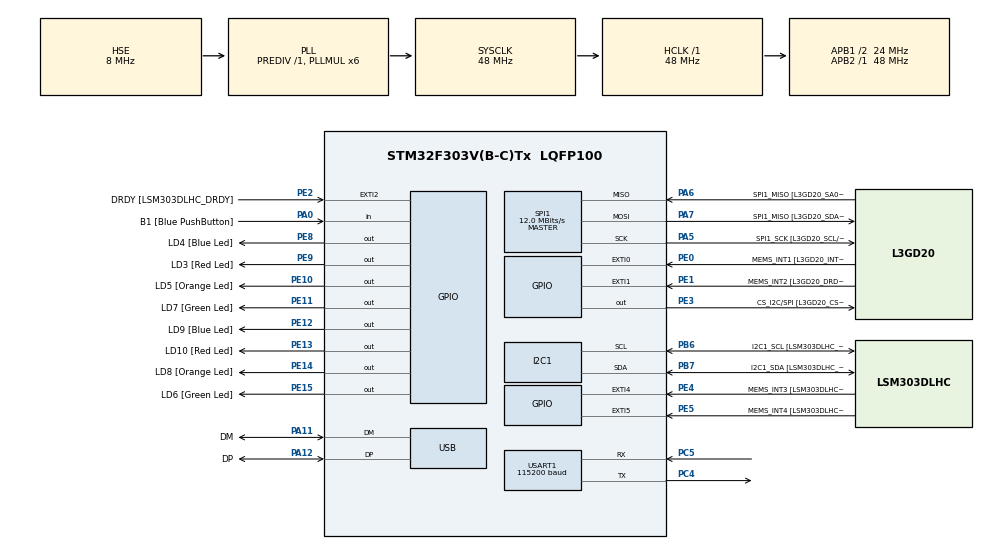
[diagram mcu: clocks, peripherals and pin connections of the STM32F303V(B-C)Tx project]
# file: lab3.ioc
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I2C1.Timing=0x00201D2B
I2C1.Timing-I2C=0x2000090E
Mcu.Family=STM32F3
Mcu.Name=STM32F303V(B-C)Tx
Mcu.Package=LQFP100
NVIC.PriorityGroup=NVIC_PRIORITYGROUP_0
NVIC.USB_LP_CAN_RX0_IRQn=true\:0\:0\:false\:false\:true\:false\:true\:true
PA0.GPIO_Label=B1 [Blue PushButton]
PA0.Signal=GPIO_Input
PA11.GPIO_Label=DM
PA11.Mode=Device
PA11.Signal=USB_DM
PA12.GPIO_Label=DP
PA12.Mode=Device
PA12.Signal=USB_DP
PA13.GPIO_Label=SWDIO
PA13.Mode=Serial_Wire
PA13.Signal=SYS_JTMS-SWDIO
PA14.GPIO_Label=SWCLK
PA14.Mode=Serial_Wire
PA14.Signal=SYS_JTCK-SWCLK
PA5.GPIO_Label=SPI1_SCK [L3GD20_SCL/SPC]
PA5.Mode=Full_Duplex_Master
PA5.Signal=SPI1_SCK
PA6.GPIO_Label=SPI1_MISO [L3GD20_SA0/SDO]
PA6.Mode=Full_Duplex_Master
PA6.Signal=SPI1_MISO
PA7.GPIO_Label=SPI1_MISO [L3GD20_SDA/SDI/SDO]
PA7.Mode=Full_Duplex_Master
PA7.Signal=SPI1_MOSI
PB3.GPIO_Label=SWO
PB3.Signal=SYS_JTDO-TRACESWO
PB6.GPIO_Label=I2C1_SCL [LSM303DLHC_SCL]
PB6.GPIO_Pu=GPIO_PULLUP
PB6.Mode=I2C
PB6.Signal=I2C1_SCL
PB7.GPIO_Label=I2C1_SDA [LSM303DLHC_SDA]
PB7.GPIO_Pu=GPIO_PULLUP
PB7.Mode=I2C
PB7.Signal=I2C1_SDA
PC14-OSC32_IN.GPIO_Label=OSC32_IN
PC14-OSC32_IN.Signal=RCC_OSC32_IN
PC15-OSC32_OUT.GPIO_Label=OSC32_OUT
PC15-OSC32_OUT.Signal=RCC_OSC32_OUT
PC4.Mode=Asynchronous
PC4.Signal=USART1_TX
PC5.Mode=Asynchronous
PC5.Signal=USART1_RX
PE0.GPIO_Label=MEMS_INT1 [L3GD20_INT1]
PE0.GPIO_ModeDefaultEXTI=GPIO_MODE_EVT_RISING
PE0.Signal=GPXTI0
PE1.GPIO_Label=MEMS_INT2 [L3GD20_DRDY/INT2]
PE1.GPIO_ModeDefaultEXTI=GPIO_MODE_EVT_RISING
PE1.Signal=GPXTI1
PE10.GPIO_Label=LD5 [Orange Led]
PE10.Signal=GPIO_Output
PE11.GPIO_Label=LD7 [Green Led]
PE11.Signal=GPIO_Output
PE12.GPIO_Label=LD9 [Blue Led]
PE12.Signal=GPIO_Output
PE13.GPIO_Label=LD10 [Red Led]
PE13.Signal=GPIO_Output
PE14.GPIO_Label=LD8 [Orange Led]
PE14.Signal=GPIO_Output
PE15.GPIO_Label=LD6 [Green Led]
PE15.Signal=GPIO_Output
PE2.GPIO_Label=DRDY [LSM303DLHC_DRDY]
PE2.GPIO_ModeDefaultEXTI=GPIO_MODE_EVT_RISING
PE2.Signal=GPXTI2
PE3.GPIO_Label=CS_I2C/SPI [L3GD20_CS_I2C/SPI]
PE3.Signal=GPIO_Output
PE4.GPIO_Label=MEMS_INT3 [LSM303DLHC_INT1]
PE4.GPIO_ModeDefaultEXTI=GPIO_MODE_EVT_RISING
PE4.Signal=GPXTI4
PE5.GPIO_Label=MEMS_INT4 [LSM303DLHC_INT2]
PE5.GPIO_ModeDefaultEXTI=GPIO_MODE_EVT_RISING
PE5.Signal=GPXTI5
PE8.GPIO_Label=LD4 [Blue Led]
PE8.Signal=GPIO_Output
PE9.GPIO_Label=LD3 [Red Led]
PE9.Signal=GPIO_Output
PF0-OSC_IN.GPIO_Label=OSC_IN
PF0-OSC_IN.Mode=HSE-External-Clock-Source
PF0-OSC_IN.Signal=RCC_OSC_IN
PF1-OSC_OUT.GPIO_Label=OSC_OUT
PF1-OSC_OUT.Signal=RCC_OSC_OUT
ProjectManager.HeapSize=0x200
ProjectManager.StackSize=0x400
ProjectManager.TargetToolchain=CMake
RCC.AHBFreq_Value=48000000
RCC.APB1CLKDivider=RCC_HCLK_DIV2
RCC.APB1Freq_Value=24000000
RCC.APB1TimFreq_Value=48000000
RCC.APB2Freq_Value=48000000
RCC.APB2TimFreq_Value=48000000
RCC.CortexFreq_Value=48000000
RCC.HCLKFreq_Value=48000000
RCC.HSE_VALUE=8000000
RCC.HSI_VALUE=8000000
RCC.LSE_VALUE=32768
RCC.PLLMUL=RCC_PLL_MUL6
RCC.SYSCLKFreq_VALUE=48000000
RCC.SYSCLKSourceVirtual=RCC_SYSCLKSOURCE_PLLCLK
RCC.USBFreq_Value=48000000
SPI1.BaudRatePrescaler=SPI_BAUDRATEPRESCALER_4
SPI1.BaudRatePrescaler-Full_Duplex_Master=SPI_BAUDRATEPRESCALER_2
SPI1.CalculateBaudRate=12.0 MBits/s
SPI1.CalculateBaudRate-Full_Duplex_Master=24.0 MBits/s
SPI1.Direction=SPI_DIRECTION_2LINES
SPI1.Mode=SPI_MODE_MASTER
SPI1.Mode-Full_Duplex_Master=SPI_MODE_MASTER
SPI1.VirtualType=VM_MASTER
USART1.BaudRate=115200
USART1.VirtualMode-Asynchronous=VM_ASYNC
USB_DEVICE.CLASS_NAME_FS=CDC
USB_DEVICE.VirtualMode=Cdc
USB_DEVICE.VirtualModeFS=Cdc_FS
VP_USB_DEVICE_VS_USB_DEVICE_CDC_FS.Mode=CDC_FS
board=STM32F3DISCOVERY

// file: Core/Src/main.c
/* USER CODE BEGIN Header */
/**
  ******************************************************************************
  * @file           : main.c
  * @brief          : Main program body
  ******************************************************************************
  * @attention
  *
  * Copyright (c) 2026 STMicroelectronics.
  * All rights reserved.
  *
  * This software is licensed under terms that can be found in the LICENSE file
  * in the root directory of this software component.
  * If no LICENSE file comes with this software, it is provided AS-IS.
  *
  ******************************************************************************
  */
/* USER CODE END Header */
#include "main.h"
#include "usb_device.h"

I2C_HandleTypeDef hi2c1;

SPI_HandleTypeDef hspi1;

UART_HandleTypeDef huart1;

void SystemClock_Config(void);
static void MX_GPIO_Init(void);
static void MX_I2C1_Init(void);
static void MX_SPI1_Init(void);
static void MX_USART1_UART_Init(void);

void display_num(int i){
  if (i == 0) {
          HAL_GPIO_WritePin(GPIOA, GPIO_PIN_1 | GPIO_PIN_2 | GPIO_PIN_3 | GPIO_PIN_4, GPIO_PIN_RESET); // a,b,d,e
          HAL_GPIO_WritePin(GPIOF, GPIO_PIN_4, GPIO_PIN_RESET);  // c
          HAL_GPIO_WritePin(GPIOC, GPIO_PIN_0, GPIO_PIN_RESET);  // f
          HAL_GPIO_WritePin(GPIOB, GPIO_PIN_1, GPIO_PIN_SET);    // g
      }

      if (i == 1) {
          HAL_GPIO_WritePin(GPIOA, GPIO_PIN_1 | GPIO_PIN_2 | GPIO_PIN_4, GPIO_PIN_SET);  // a,e,d
          HAL_GPIO_WritePin(GPIOA, GPIO_PIN_3, GPIO_PIN_RESET); // b
          HAL_GPIO_WritePin(GPIOF, GPIO_PIN_4, GPIO_PIN_RESET); // c
          HAL_GPIO_WritePin(GPIOC, GPIO_PIN_0, GPIO_PIN_SET);   // f
          HAL_GPIO_WritePin(GPIOB, GPIO_PIN_1, GPIO_PIN_SET);   // g
      }

      if (i == 2) {
          HAL_GPIO_WritePin(GPIOA, GPIO_PIN_1 | GPIO_PIN_3 | GPIO_PIN_4, GPIO_PIN_RESET); // a,b,d
          HAL_GPIO_WritePin(GPIOA, GPIO_PIN_2, GPIO_PIN_RESET);  // e
          HAL_GPIO_WritePin(GPIOF, GPIO_PIN_4, GPIO_PIN_SET);  // c
          HAL_GPIO_WritePin(GPIOC, GPIO_PIN_0, GPIO_PIN_SET);    // f
          HAL_GPIO_WritePin(GPIOB, GPIO_PIN_1, GPIO_PIN_RESET);  // g
      }

      if (i == 3) {
          HAL_GPIO_WritePin(GPIOA, GPIO_PIN_1 | GPIO_PIN_3 | GPIO_PIN_4, GPIO_PIN_RESET); // a,b,d
          HAL_GPIO_WritePin(GPIOA, GPIO_PIN_2, GPIO_PIN_SET);    // e
          HAL_GPIO_WritePin(GPIOF, GPIO_PIN_4, GPIO_PIN_RESET);  // c
          HAL_GPIO_WritePin(GPIOC, GPIO_PIN_0, GPIO_PIN_SET);  // f
          HAL_GPIO_WritePin(GPIOB, GPIO_PIN_1, GPIO_PIN_RESET);  // g
      }

      if (i == 4) {
          HAL_GPIO_WritePin(GPIOA, GPIO_PIN_1, GPIO_PIN_SET);
          HAL_GPIO_WritePin(GPIOA, GPIO_PIN_3, GPIO_PIN_RESET); // a,b
          HAL_GPIO_WritePin(GPIOA, GPIO_PIN_4 | GPIO_PIN_2, GPIO_PIN_SET);   // d,e
          HAL_GPIO_WritePin(GPIOF, GPIO_PIN_4, GPIO_PIN_RESET);               // c
          HAL_GPIO_WritePin(GPIOC, GPIO_PIN_0, GPIO_PIN_RESET);               // f
          HAL_GPIO_WritePin(GPIOB, GPIO_PIN_1, GPIO_PIN_RESET);               // g
      }

      if (i == 5) {
          HAL_GPIO_WritePin(GPIOA, GPIO_PIN_1 | GPIO_PIN_4, GPIO_PIN_RESET); // a,d
          HAL_GPIO_WritePin(GPIOA, GPIO_PIN_2 | GPIO_PIN_3, GPIO_PIN_SET);   // e,b
          HAL_GPIO_WritePin(GPIOF, GPIO_PIN_4, GPIO_PIN_RESET);               // c
          HAL_GPIO_WritePin(GPIOC, GPIO_PIN_0, GPIO_PIN_RESET);               // f
          HAL_GPIO_WritePin(GPIOB, GPIO_PIN_1, GPIO_PIN_RESET);               // g
      }

      if (i == 6) {
          HAL_GPIO_WritePin(GPIOA, GPIO_PIN_1 | GPIO_PIN_4, GPIO_PIN_RESET); // a,d
          HAL_GPIO_WritePin(GPIOA, GPIO_PIN_3, GPIO_PIN_SET);
          HAL_GPIO_WritePin(GPIOA, GPIO_PIN_2, GPIO_PIN_RESET);   // e,b
          HAL_GPIO_WritePin(GPIOF, GPIO_PIN_4, GPIO_PIN_RESET);               // c
          HAL_GPIO_WritePin(GPIOC, GPIO_PIN_0, GPIO_PIN_RESET);               // f
          HAL_GPIO_WritePin(GPIOB, GPIO_PIN_1, GPIO_PIN_RESET);               // g
      }

      if (i == 7) {
          HAL_GPIO_WritePin(GPIOA, GPIO_PIN_1 | GPIO_PIN_3, GPIO_PIN_RESET);
          HAL_GPIO_WritePin(GPIOA, GPIO_PIN_4 | GPIO_PIN_2, GPIO_PIN_SET); // a,b,c,d
          HAL_GPIO_WritePin(GPIOF, GPIO_PIN_4, GPIO_PIN_RESET);               // c
          HAL_GPIO_WritePin(GPIOC, GPIO_PIN_0, GPIO_PIN_SET);                 // f
          HAL_GPIO_WritePin(GPIOB, GPIO_PIN_1, GPIO_PIN_SET);                 // g
      }

      if (i == 8) {
          HAL_GPIO_WritePin(GPIOA, GPIO_PIN_1 | GPIO_PIN_2 | GPIO_PIN_3 | GPIO_PIN_4, GPIO_PIN_RESET); // a,b,d,e
          HAL_GPIO_WritePin(GPIOF, GPIO_PIN_4, GPIO_PIN_RESET);               // c
          HAL_GPIO_WritePin(GPIOC, GPIO_PIN_0, GPIO_PIN_RESET);               // f
          HAL_GPIO_WritePin(GPIOB, GPIO_PIN_1, GPIO_PIN_RESET);               // g
      }

      if (i == 9) {
          HAL_GPIO_WritePin(GPIOA, GPIO_PIN_1 | GPIO_PIN_3 | GPIO_PIN_4, GPIO_PIN_RESET); // a,b,d
          HAL_GPIO_WritePin(GPIOA, GPIO_PIN_2, GPIO_PIN_SET);    // e
          HAL_GPIO_WritePin(GPIOF, GPIO_PIN_4, GPIO_PIN_RESET);  // c
          HAL_GPIO_WritePin(GPIOC, GPIO_PIN_0, GPIO_PIN_RESET);  // f
          HAL_GPIO_WritePin(GPIOB, GPIO_PIN_1, GPIO_PIN_RESET);  // g
      }

      if (i == 10) { // A
          HAL_GPIO_WritePin(GPIOA, GPIO_PIN_1 | GPIO_PIN_3 | GPIO_PIN_2, GPIO_PIN_RESET); // a,b,e
          HAL_GPIO_WritePin(GPIOA, GPIO_PIN_4, GPIO_PIN_SET);    // d
          HAL_GPIO_WritePin(GPIOF, GPIO_PIN_4, GPIO_PIN_RESET);  // c
          HAL_GPIO_WritePin(GPIOC, GPIO_PIN_0, GPIO_PIN_RESET);  // f
          HAL_GPIO_WritePin(GPIOB, GPIO_PIN_1, GPIO_PIN_RESET);  // g
      }

      if (i == 11) { // b
          HAL_GPIO_WritePin(GPIOA, GPIO_PIN_4, GPIO_PIN_RESET);  // d
          HAL_GPIO_WritePin(GPIOA, GPIO_PIN_1 | GPIO_PIN_3, GPIO_PIN_SET);
          HAL_GPIO_WritePin(GPIOA, GPIO_PIN_2, GPIO_PIN_RESET); // a,b,e
          HAL_GPIO_WritePin(GPIOF, GPIO_PIN_4, GPIO_PIN_RESET);  // c
          HAL_GPIO_WritePin(GPIOC, GPIO_PIN_0, GPIO_PIN_RESET);  // f
          HAL_GPIO_WritePin(GPIOB, GPIO_PIN_1, GPIO_PIN_RESET);  // g
      }

      if (i == 12) { // C
          HAL_GPIO_WritePin(GPIOA, GPIO_PIN_1 | GPIO_PIN_4 | GPIO_PIN_2, GPIO_PIN_RESET); // a,d,e
          HAL_GPIO_WritePin(GPIOA, GPIO_PIN_3, GPIO_PIN_SET);    // b
          HAL_GPIO_WritePin(GPIOF, GPIO_PIN_4, GPIO_PIN_SET);    // c
          HAL_GPIO_WritePin(GPIOC, GPIO_PIN_0, GPIO_PIN_RESET);  // f
          HAL_GPIO_WritePin(GPIOB, GPIO_PIN_1, GPIO_PIN_SET);    // g
      }

      if (i == 13) { // d
          HAL_GPIO_WritePin(GPIOA, GPIO_PIN_3 | GPIO_PIN_4 | GPIO_PIN_2, GPIO_PIN_RESET); // b,d,e
          HAL_GPIO_WritePin(GPIOA, GPIO_PIN_1, GPIO_PIN_SET);    // a
          HAL_GPIO_WritePin(GPIOF, GPIO_PIN_4, GPIO_PIN_RESET);  // c
          HAL_GPIO_WritePin(GPIOC, GPIO_PIN_0, GPIO_PIN_SET);    // f
          HAL_GPIO_WritePin(GPIOB, GPIO_PIN_1, GPIO_PIN_RESET);  // g
      }

      if (i == 14) { // E
          HAL_GPIO_WritePin(GPIOA, GPIO_PIN_1 | GPIO_PIN_4 | GPIO_PIN_2, GPIO_PIN_RESET); // a,d,e
          HAL_GPIO_WritePin(GPIOA, GPIO_PIN_3, GPIO_PIN_SET);    // b
          HAL_GPIO_WritePin(GPIOF, GPIO_PIN_4, GPIO_PIN_SET);    // c
          HAL_GPIO_WritePin(GPIOC, GPIO_PIN_0, GPIO_PIN_RESET);  // f
          HAL_GPIO_WritePin(GPIOB, GPIO_PIN_1, GPIO_PIN_RESET);  // g
      }

      if (i == 15) { // F
          HAL_GPIO_WritePin(GPIOA, GPIO_PIN_1 | GPIO_PIN_2, GPIO_PIN_RESET); // a,d,e
          HAL_GPIO_WritePin(GPIOA, GPIO_PIN_4, GPIO_PIN_SET);
          HAL_GPIO_WritePin(GPIOA, GPIO_PIN_3, GPIO_PIN_SET);    // b
          HAL_GPIO_WritePin(GPIOF, GPIO_PIN_4, GPIO_PIN_SET);    // c
          HAL_GPIO_WritePin(GPIOC, GPIO_PIN_0, GPIO_PIN_RESET);  // f
          HAL_GPIO_WritePin(GPIOB, GPIO_PIN_1, GPIO_PIN_RESET);    // g
      }
}

int main(void)
{

  /* MCU Configuration--------------------------------------------------------*/

  /* Reset of all peripherals, Initializes the Flash interface and the Systick. */
  HAL_Init();

  /* Configure the system clock */
  SystemClock_Config();

  /* Initialize all configured peripherals */
  MX_GPIO_Init();
  MX_I2C1_Init();
  MX_SPI1_Init();
  MX_USART1_UART_Init();
  MX_USB_DEVICE_Init();
  /*HAL_GPIO_WritePin(GPIOA, GPIO_PIN_1 | GPIO_PIN_2 | GPIO_PIN_3 | GPIO_PIN_4, GPIO_PIN_RESET);
  HAL_GPIO_WritePin(GPIOF, GPIO_PIN_4, GPIO_PIN_RESET);
  HAL_GPIO_WritePin(GPIOC, GPIO_PIN_0, GPIO_PIN_RESET);
  HAL_GPIO_WritePin(GPIOB, GPIO_PIN_1, GPIO_PIN_RESET);*/

  //a = PA1 b = PA3 c = PF4 d = PA4 e = PA2 f = PC0 g = PB1
  /* Infinite loop */
  /* USER CODE BEGIN WHILE */

  int n = 0;
  while (1)
  {
    display_num(n);
    /* USER CODE END WHILE */

    if(HAL_GPIO_ReadPin(GPIOB, GPIO_PIN_4) == GPIO_PIN_SET) { // active-low
        HAL_Delay(50); // debounce
        if(HAL_GPIO_ReadPin(GPIOB, GPIO_PIN_4) == GPIO_PIN_SET) {
            n = (rand() % 6) + 1;
            while(HAL_GPIO_ReadPin(GPIOB, GPIO_PIN_4) == GPIO_PIN_SET); // wait for release
            HAL_Delay(50); // debounce
        }
    }
  }

}

void SystemClock_Config(void)
{
  RCC_OscInitTypeDef RCC_OscInitStruct = {0};
  RCC_ClkInitTypeDef RCC_ClkInitStruct = {0};
  RCC_PeriphCLKInitTypeDef PeriphClkInit = {0};

  /** Initializes the RCC Oscillators according to the specified parameters
  * in the RCC_OscInitTypeDef structure.
  */
  RCC_OscInitStruct.OscillatorType = RCC_OSCILLATORTYPE_HSI|RCC_OSCILLATORTYPE_HSE;
  RCC_OscInitStruct.HSEState = RCC_HSE_BYPASS;
  RCC_OscInitStruct.HSEPredivValue = RCC_HSE_PREDIV_DIV1;
  RCC_OscInitStruct.HSIState = RCC_HSI_ON;
  RCC_OscInitStruct.HSICalibrationValue = RCC_HSICALIBRATION_DEFAULT;
  RCC_OscInitStruct.PLL.PLLState = RCC_PLL_ON;
  RCC_OscInitStruct.PLL.PLLSource = RCC_PLLSOURCE_HSE;
  RCC_OscInitStruct.PLL.PLLMUL = RCC_PLL_MUL6;
  if (HAL_RCC_OscConfig(&RCC_OscInitStruct) != HAL_OK)
  {
    Error_Handler();
  }

  /** Initializes the CPU, AHB and APB buses clocks
  */
  RCC_ClkInitStruct.ClockType = RCC_CLOCKTYPE_HCLK|RCC_CLOCKTYPE_SYSCLK
                              |RCC_CLOCKTYPE_PCLK1|RCC_CLOCKTYPE_PCLK2;
  RCC_ClkInitStruct.SYSCLKSource = RCC_SYSCLKSOURCE_PLLCLK;
  RCC_ClkInitStruct.AHBCLKDivider = RCC_SYSCLK_DIV1;
  RCC_ClkInitStruct.APB1CLKDivider = RCC_HCLK_DIV2;
  RCC_ClkInitStruct.APB2CLKDivider = RCC_HCLK_DIV1;

  if (HAL_RCC_ClockConfig(&RCC_ClkInitStruct, FLASH_LATENCY_1) != HAL_OK)
  {
    Error_Handler();
  }
  PeriphClkInit.PeriphClockSelection = RCC_PERIPHCLK_USB|RCC_PERIPHCLK_USART1
                              |RCC_PERIPHCLK_I2C1;
  PeriphClkInit.Usart1ClockSelection = RCC_USART1CLKSOURCE_PCLK2;
  PeriphClkInit.I2c1ClockSelection = RCC_I2C1CLKSOURCE_HSI;
  PeriphClkInit.USBClockSelection = RCC_USBCLKSOURCE_PLL;
  if (HAL_RCCEx_PeriphCLKConfig(&PeriphClkInit) != HAL_OK)
  {
    Error_Handler();
  }
}

static void MX_I2C1_Init(void)
{

  hi2c1.Instance = I2C1;
  hi2c1.Init.Timing = 0x00201D2B;
  hi2c1.Init.OwnAddress1 = 0;
  hi2c1.Init.AddressingMode = I2C_ADDRESSINGMODE_7BIT;
  hi2c1.Init.DualAddressMode = I2C_DUALADDRESS_DISABLE;
  hi2c1.Init.OwnAddress2 = 0;
  hi2c1.Init.OwnAddress2Masks = I2C_OA2_NOMASK;
  hi2c1.Init.GeneralCallMode = I2C_GENERALCALL_DISABLE;
  hi2c1.Init.NoStretchMode = I2C_NOSTRETCH_DISABLE;
  if (HAL_I2C_Init(&hi2c1) != HAL_OK)
  {
    Error_Handler();
  }

  /** Configure Analogue filter
  */
  if (HAL_I2CEx_ConfigAnalogFilter(&hi2c1, I2C_ANALOGFILTER_ENABLE) != HAL_OK)
  {
    Error_Handler();
  }

  /** Configure Digital filter
  */
  if (HAL_I2CEx_ConfigDigitalFilter(&hi2c1, 0) != HAL_OK)
  {
    Error_Handler();
  }

}

static void MX_SPI1_Init(void)
{

  /* SPI1 parameter configuration*/
  hspi1.Instance = SPI1;
  hspi1.Init.Mode = SPI_MODE_MASTER;
  hspi1.Init.Direction = SPI_DIRECTION_2LINES;
  hspi1.Init.DataSize = SPI_DATASIZE_4BIT;
  hspi1.Init.CLKPolarity = SPI_POLARITY_LOW;
  hspi1.Init.CLKPhase = SPI_PHASE_1EDGE;
  hspi1.Init.NSS = SPI_NSS_SOFT;
  hspi1.Init.BaudRatePrescaler = SPI_BAUDRATEPRESCALER_4;
  hspi1.Init.FirstBit = SPI_FIRSTBIT_MSB;
  hspi1.Init.TIMode = SPI_TIMODE_DISABLE;
  hspi1.Init.CRCCalculation = SPI_CRCCALCULATION_DISABLE;
  hspi1.Init.CRCPolynomial = 7;
  hspi1.Init.CRCLength = SPI_CRC_LENGTH_DATASIZE;
  hspi1.Init.NSSPMode = SPI_NSS_PULSE_ENABLE;
  if (HAL_SPI_Init(&hspi1) != HAL_OK)
  {
    Error_Handler();
  }

}

static void MX_USART1_UART_Init(void)
{

  huart1.Instance = USART1;
  huart1.Init.BaudRate = 115200;
  huart1.Init.WordLength = UART_WORDLENGTH_8B;
  huart1.Init.StopBits = UART_STOPBITS_1;
  huart1.Init.Parity = UART_PARITY_NONE;
  huart1.Init.Mode = UART_MODE_TX_RX;
  huart1.Init.HwFlowCtl = UART_HWCONTROL_NONE;
  huart1.Init.OverSampling = UART_OVERSAMPLING_16;
  huart1.Init.OneBitSampling = UART_ONE_BIT_SAMPLE_DISABLE;
  huart1.AdvancedInit.AdvFeatureInit = UART_ADVFEATURE_NO_INIT;
  if (HAL_UART_Init(&huart1) != HAL_OK)
  {
    Error_Handler();
  }

}

static void MX_GPIO_Init(void)
{
  GPIO_InitTypeDef GPIO_InitStruct = {0};
  /* USER CODE BEGIN MX_GPIO_Init_1 */
  /* USER CODE BEGIN MX_GPIO_Init_2 */

/* USER CODE END MX_GPIO_Init_2 */

  /* USER CODE END MX_GPIO_Init_1 */

  /* GPIO Ports Clock Enable */
  __HAL_RCC_GPIOE_CLK_ENABLE();
  __HAL_RCC_GPIOC_CLK_ENABLE();
  __HAL_RCC_GPIOF_CLK_ENABLE();
  __HAL_RCC_GPIOA_CLK_ENABLE();
  __HAL_RCC_GPIOB_CLK_ENABLE();

  GPIO_InitStruct.Pin = GPIO_PIN_1 | GPIO_PIN_2 | GPIO_PIN_3 | GPIO_PIN_4;
  GPIO_InitStruct.Mode = GPIO_MODE_OUTPUT_PP;
  GPIO_InitStruct.Pull = GPIO_NOPULL;
  GPIO_InitStruct.Speed = GPIO_SPEED_FREQ_LOW;
  HAL_GPIO_Init(GPIOA, &GPIO_InitStruct);

  /* -------- GPIOF : PF4 -------- */
  GPIO_InitStruct.Pin = GPIO_PIN_4;
  HAL_GPIO_Init(GPIOF, &GPIO_InitStruct);

  /* -------- GPIOC : PC0 -------- */
  GPIO_InitStruct.Pin = GPIO_PIN_0;
  HAL_GPIO_Init(GPIOC, &GPIO_InitStruct);

  /* -------- GPIOB : PB1 -------- */
  GPIO_InitStruct.Pin = GPIO_PIN_1;
  HAL_GPIO_Init(GPIOB, &GPIO_InitStruct);

  //PB4
  GPIO_InitStruct.Pin = GPIO_PIN_4;
  GPIO_InitStruct.Mode = GPIO_MODE_INPUT;    // Input mode
  GPIO_InitStruct.Pull = GPIO_PULLDOWN;        // No internal pull-up or pull-down
  HAL_GPIO_Init(GPIOB, &GPIO_InitStruct);

  /*Configure GPIO pin Output Level */
  HAL_GPIO_WritePin(GPIOE, CS_I2C_SPI_Pin|LD4_Pin|LD3_Pin|LD5_Pin
                          |LD7_Pin|LD9_Pin|LD10_Pin|LD8_Pin
                          |LD6_Pin, GPIO_PIN_RESET);

  /*Configure GPIO pins : DRDY_Pin MEMS_INT3_Pin MEMS_INT4_Pin MEMS_INT1_Pin
                           MEMS_INT2_Pin */
  GPIO_InitStruct.Pin = DRDY_Pin|MEMS_INT3_Pin|MEMS_INT4_Pin|MEMS_INT1_Pin
                          |MEMS_INT2_Pin;
  GPIO_InitStruct.Mode = GPIO_MODE_EVT_RISING;
  GPIO_InitStruct.Pull = GPIO_NOPULL;
  HAL_GPIO_Init(GPIOE, &GPIO_InitStruct);

  /*Configure GPIO pins : CS_I2C_SPI_Pin LD4_Pin LD3_Pin LD5_Pin
                           LD7_Pin LD9_Pin LD10_Pin LD8_Pin
                           LD6_Pin */
  GPIO_InitStruct.Pin = CS_I2C_SPI_Pin|LD4_Pin|LD3_Pin|LD5_Pin
                          |LD7_Pin|LD9_Pin|LD10_Pin|LD8_Pin
                          |LD6_Pin;
  GPIO_InitStruct.Mode = GPIO_MODE_OUTPUT_PP;
  GPIO_InitStruct.Pull = GPIO_NOPULL;
  GPIO_InitStruct.Speed = GPIO_SPEED_FREQ_LOW;
  HAL_GPIO_Init(GPIOE, &GPIO_InitStruct);

  /*Configure GPIO pin : B1_Pin */
  GPIO_InitStruct.Pin = B1_Pin;
  GPIO_InitStruct.Mode = GPIO_MODE_INPUT;
  GPIO_InitStruct.Pull = GPIO_NOPULL;
  HAL_GPIO_Init(B1_GPIO_Port, &GPIO_InitStruct);

}

void Error_Handler(void)
{
  __disable_irq();
  while (1)
  {
  }
}
